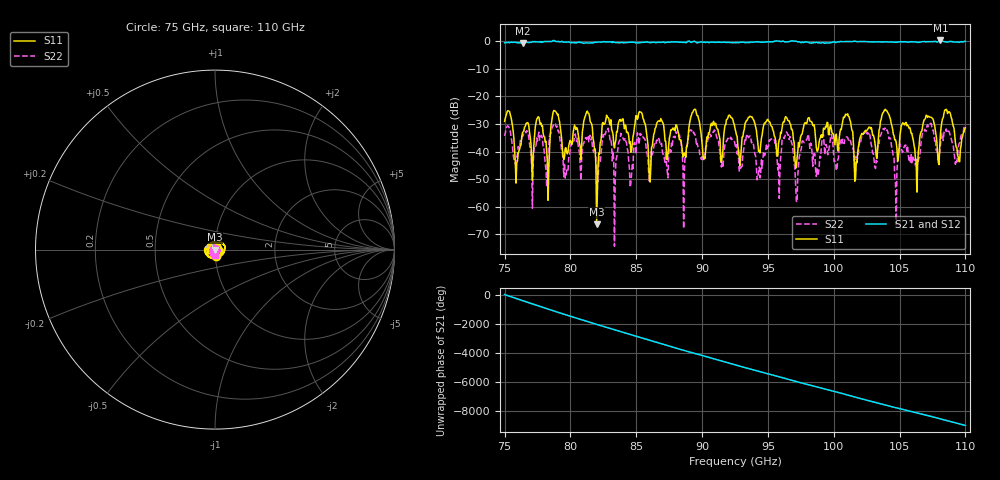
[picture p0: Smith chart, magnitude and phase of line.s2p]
!Created with skrf (http://scikit-rf.org).
# GHz S RI R 50.0
!freq ReS11 ImS11 ReS21 ImS21 ReS12 ImS12 ReS22 ImS22
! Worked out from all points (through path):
!   647 points, 75 GHz to 110 GHz, reference 50 ohm
!   highest |S21| = 0.21 dB at 108.1 GHz (marker M1); lowest = -0.8 dB at 76.41 GHz (marker M2)
!   lowest |S11| = -66.3 dB at 81.99 GHz (marker M3), VSWR 1.00, Z = 50 + j0.021 ohm
!   |S11| at or under -10 dB: start of sweep to end of sweep
!   |S22| runs from -74.2 to -29.8 dB; largest |S21 - S12| = 0.014
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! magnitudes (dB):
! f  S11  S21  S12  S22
! 75 GHz  -29.1  -0.6  -0.6  -34.3
! 75.92 GHz  -44.1  -0.6  -0.6  -41.9
! 76.41 GHz  -32.8  -0.8  -0.8  -34.2
! 80.85 GHz  -38.1  -0.6  -0.6  -42.6
! 81.4 GHz  -26.2  -0.8  -0.8  -36.5
! 81.99 GHz  -66.3  -0.5  -0.5  -48.2
! 82.75 GHz  -26.8  -0.3  -0.3  -31.9
! 83.35 GHz  -38.7  -0.5  -0.5  -74.2
! 85.35 GHz  -25.7  -0.5  -0.5  -34.0
! 86.05 GHz  -51.0  -0.6  -0.6  -48.7
! 86.7 GHz  -28.9  -0.4  -0.4  -35.3
! 92.5 GHz  -31.6  -0.6  -0.6  -37.3
! 94.29 GHz  -39.9  -0.3  -0.3  -47.8
! 96.51 GHz  -28.7  -0.3  -0.3  -34.0
! 97.21 GHz  -42.4  -0.2  -0.2  -58.3
! 98.35 GHz  -29.5  -0.6  -0.6  -40.4
! 101.1 GHz  -26.3  -0.2  -0.2  -34.9
! 101.7 GHz  -43.6  -0.2  -0.2  -41.7
! 104.2 GHz  -26.7  -0.4  -0.4  -35.4
! 104.7 GHz  -35.8  -0.5  -0.4  -51.2
! 108.1 GHz  -33.5  0.2  0.2  -37.6
! 110 GHz  -31.4  -0.1  -0.1  -30.9
